VERSION 5.7 ;
  NOWIREEXTENSIONATPIN ON ;
  DIVIDERCHAR "/" ;
  BUSBITCHARS "[]" ;
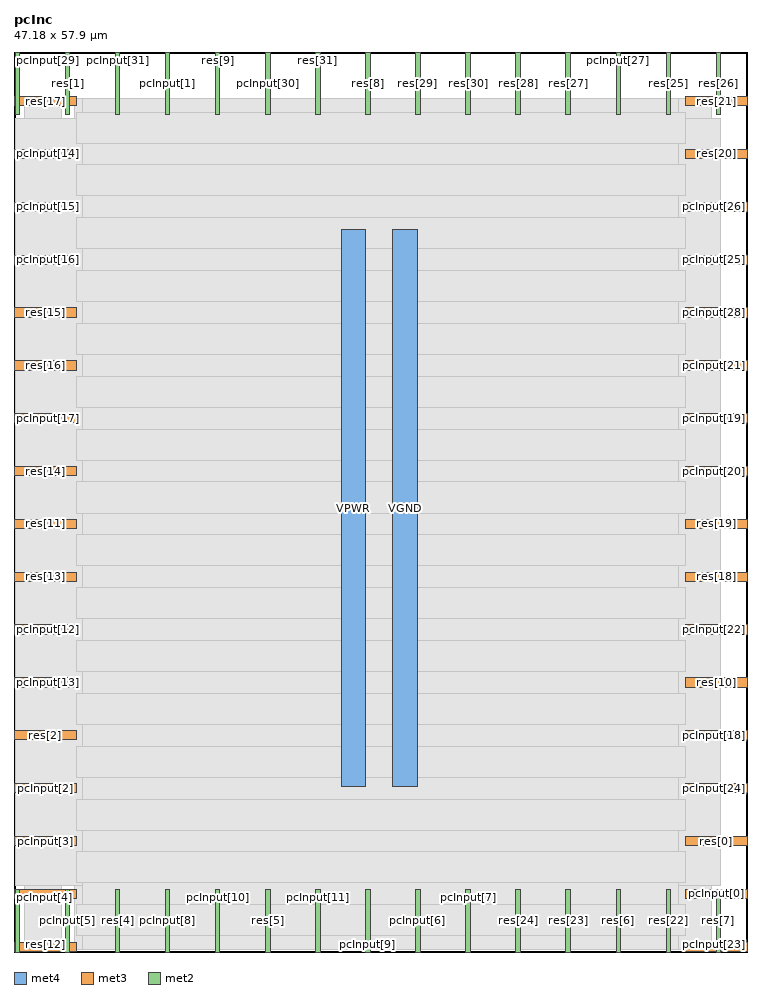
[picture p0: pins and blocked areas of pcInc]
MACRO pcInc
  CLASS BLOCK ;
  FOREIGN pcInc ;
  ORIGIN 0.000 0.000 ;
  SIZE 47.180 BY 57.900 ;
  PIN VGND
    DIRECTION INOUT ;
    USE GROUND ;
    PORT
      LAYER met4 ;
        RECT 24.340 10.640 25.940 46.480 ;
    END
  END VGND
  PIN VPWR
    DIRECTION INOUT ;
    USE POWER ;
    PORT
      LAYER met4 ;
        RECT 21.040 10.640 22.640 46.480 ;
    END
  END VPWR
  PIN pcInput[0]
    DIRECTION INPUT ;
    USE SIGNAL ;
    ANTENNAGATEAREA 0.196500 ;
    PORT
      LAYER met3 ;
        RECT 43.180 3.440 47.180 4.040 ;
    END
  END pcInput[0]
  PIN pcInput[10]
    DIRECTION INPUT ;
    USE SIGNAL ;
    ANTENNAGATEAREA 0.196500 ;
    PORT
      LAYER met2 ;
        RECT 12.970 0.000 13.250 4.000 ;
    END
  END pcInput[10]
  PIN pcInput[11]
    DIRECTION INPUT ;
    USE SIGNAL ;
    ANTENNAGATEAREA 0.196500 ;
    PORT
      LAYER met2 ;
        RECT 19.410 0.000 19.690 4.000 ;
    END
  END pcInput[11]
  PIN pcInput[12]
    DIRECTION INPUT ;
    USE SIGNAL ;
    ANTENNAGATEAREA 0.196500 ;
    PORT
      LAYER met3 ;
        RECT 0.000 20.440 4.000 21.040 ;
    END
  END pcInput[12]
  PIN pcInput[13]
    DIRECTION INPUT ;
    USE SIGNAL ;
    ANTENNAGATEAREA 0.196500 ;
    PORT
      LAYER met3 ;
        RECT 0.000 17.040 4.000 17.640 ;
    END
  END pcInput[13]
  PIN pcInput[14]
    DIRECTION INPUT ;
    USE SIGNAL ;
    ANTENNAGATEAREA 0.196500 ;
    PORT
      LAYER met3 ;
        RECT 0.000 51.040 4.000 51.640 ;
    END
  END pcInput[14]
  PIN pcInput[15]
    DIRECTION INPUT ;
    USE SIGNAL ;
    ANTENNAGATEAREA 0.196500 ;
    PORT
      LAYER met3 ;
        RECT 0.000 47.640 4.000 48.240 ;
    END
  END pcInput[15]
  PIN pcInput[16]
    DIRECTION INPUT ;
    USE SIGNAL ;
    ANTENNAGATEAREA 0.196500 ;
    PORT
      LAYER met3 ;
        RECT 0.000 44.240 4.000 44.840 ;
    END
  END pcInput[16]
  PIN pcInput[17]
    DIRECTION INPUT ;
    USE SIGNAL ;
    ANTENNAGATEAREA 0.196500 ;
    PORT
      LAYER met3 ;
        RECT 0.000 34.040 4.000 34.640 ;
    END
  END pcInput[17]
  PIN pcInput[18]
    DIRECTION INPUT ;
    USE SIGNAL ;
    ANTENNAGATEAREA 0.196500 ;
    PORT
      LAYER met3 ;
        RECT 43.180 13.640 47.180 14.240 ;
    END
  END pcInput[18]
  PIN pcInput[19]
    DIRECTION INPUT ;
    USE SIGNAL ;
    ANTENNAGATEAREA 0.196500 ;
    PORT
      LAYER met3 ;
        RECT 43.180 34.040 47.180 34.640 ;
    END
  END pcInput[19]
  PIN pcInput[1]
    DIRECTION INPUT ;
    USE SIGNAL ;
    ANTENNAGATEAREA 0.196500 ;
    PORT
      LAYER met2 ;
        RECT 9.750 53.900 10.030 57.900 ;
    END
  END pcInput[1]
  PIN pcInput[20]
    DIRECTION INPUT ;
    USE SIGNAL ;
    ANTENNAGATEAREA 0.196500 ;
    PORT
      LAYER met3 ;
        RECT 43.180 30.640 47.180 31.240 ;
    END
  END pcInput[20]
  PIN pcInput[21]
    DIRECTION INPUT ;
    USE SIGNAL ;
    ANTENNAGATEAREA 0.196500 ;
    PORT
      LAYER met3 ;
        RECT 43.180 37.440 47.180 38.040 ;
    END
  END pcInput[21]
  PIN pcInput[22]
    DIRECTION INPUT ;
    USE SIGNAL ;
    ANTENNAGATEAREA 0.196500 ;
    PORT
      LAYER met3 ;
        RECT 43.180 20.440 47.180 21.040 ;
    END
  END pcInput[22]
  PIN pcInput[23]
    DIRECTION INPUT ;
    USE SIGNAL ;
    ANTENNAGATEAREA 0.196500 ;
    PORT
      LAYER met3 ;
        RECT 43.180 0.040 47.180 0.640 ;
    END
  END pcInput[23]
  PIN pcInput[24]
    DIRECTION INPUT ;
    USE SIGNAL ;
    ANTENNAGATEAREA 0.196500 ;
    PORT
      LAYER met3 ;
        RECT 43.180 10.240 47.180 10.840 ;
    END
  END pcInput[24]
  PIN pcInput[25]
    DIRECTION INPUT ;
    USE SIGNAL ;
    ANTENNAGATEAREA 0.196500 ;
    PORT
      LAYER met3 ;
        RECT 43.180 44.240 47.180 44.840 ;
    END
  END pcInput[25]
  PIN pcInput[26]
    DIRECTION INPUT ;
    USE SIGNAL ;
    ANTENNAGATEAREA 0.196500 ;
    PORT
      LAYER met3 ;
        RECT 43.180 47.640 47.180 48.240 ;
    END
  END pcInput[26]
  PIN pcInput[27]
    DIRECTION INPUT ;
    USE SIGNAL ;
    ANTENNAGATEAREA 0.196500 ;
    PORT
      LAYER met2 ;
        RECT 38.730 53.900 39.010 57.900 ;
    END
  END pcInput[27]
  PIN pcInput[28]
    DIRECTION INPUT ;
    USE SIGNAL ;
    ANTENNAGATEAREA 0.196500 ;
    PORT
      LAYER met3 ;
        RECT 43.180 40.840 47.180 41.440 ;
    END
  END pcInput[28]
  PIN pcInput[29]
    DIRECTION INPUT ;
    USE SIGNAL ;
    ANTENNAGATEAREA 0.196500 ;
    PORT
      LAYER met2 ;
        RECT 0.090 53.900 0.370 57.900 ;
    END
  END pcInput[29]
  PIN pcInput[2]
    DIRECTION INPUT ;
    USE SIGNAL ;
    ANTENNAGATEAREA 0.126000 ;
    PORT
      LAYER met3 ;
        RECT 0.000 10.240 4.000 10.840 ;
    END
  END pcInput[2]
  PIN pcInput[30]
    DIRECTION INPUT ;
    USE SIGNAL ;
    ANTENNAGATEAREA 0.196500 ;
    PORT
      LAYER met2 ;
        RECT 16.190 53.900 16.470 57.900 ;
    END
  END pcInput[30]
  PIN pcInput[31]
    DIRECTION INPUT ;
    USE SIGNAL ;
    ANTENNAGATEAREA 0.196500 ;
    PORT
      LAYER met2 ;
        RECT 6.530 53.900 6.810 57.900 ;
    END
  END pcInput[31]
  PIN pcInput[3]
    DIRECTION INPUT ;
    USE SIGNAL ;
    ANTENNAGATEAREA 0.196500 ;
    PORT
      LAYER met3 ;
        RECT 0.000 6.840 4.000 7.440 ;
    END
  END pcInput[3]
  PIN pcInput[4]
    DIRECTION INPUT ;
    USE SIGNAL ;
    ANTENNAGATEAREA 0.196500 ;
    PORT
      LAYER met2 ;
        RECT 0.090 0.000 0.370 4.000 ;
    END
  END pcInput[4]
  PIN pcInput[5]
    DIRECTION INPUT ;
    USE SIGNAL ;
    ANTENNAGATEAREA 0.196500 ;
    PORT
      LAYER met2 ;
        RECT 3.310 0.000 3.590 4.000 ;
    END
  END pcInput[5]
  PIN pcInput[6]
    DIRECTION INPUT ;
    USE SIGNAL ;
    ANTENNAGATEAREA 0.196500 ;
    PORT
      LAYER met2 ;
        RECT 25.850 0.000 26.130 4.000 ;
    END
  END pcInput[6]
  PIN pcInput[7]
    DIRECTION INPUT ;
    USE SIGNAL ;
    ANTENNAGATEAREA 0.196500 ;
    PORT
      LAYER met2 ;
        RECT 29.070 0.000 29.350 4.000 ;
    END
  END pcInput[7]
  PIN pcInput[8]
    DIRECTION INPUT ;
    USE SIGNAL ;
    ANTENNAGATEAREA 0.196500 ;
    PORT
      LAYER met2 ;
        RECT 9.750 0.000 10.030 4.000 ;
    END
  END pcInput[8]
  PIN pcInput[9]
    DIRECTION INPUT ;
    USE SIGNAL ;
    ANTENNAGATEAREA 0.196500 ;
    PORT
      LAYER met2 ;
        RECT 22.630 0.000 22.910 4.000 ;
    END
  END pcInput[9]
  PIN res[0]
    DIRECTION OUTPUT ;
    USE SIGNAL ;
    ANTENNADIFFAREA 0.445500 ;
    PORT
      LAYER met3 ;
        RECT 43.180 6.840 47.180 7.440 ;
    END
  END res[0]
  PIN res[10]
    DIRECTION OUTPUT ;
    USE SIGNAL ;
    ANTENNADIFFAREA 0.445500 ;
    PORT
      LAYER met3 ;
        RECT 43.180 17.040 47.180 17.640 ;
    END
  END res[10]
  PIN res[11]
    DIRECTION OUTPUT ;
    USE SIGNAL ;
    ANTENNADIFFAREA 0.445500 ;
    PORT
      LAYER met3 ;
        RECT 0.000 27.240 4.000 27.840 ;
    END
  END res[11]
  PIN res[12]
    DIRECTION OUTPUT ;
    USE SIGNAL ;
    ANTENNADIFFAREA 0.445500 ;
    PORT
      LAYER met3 ;
        RECT 0.000 0.040 4.000 0.640 ;
    END
  END res[12]
  PIN res[13]
    DIRECTION OUTPUT ;
    USE SIGNAL ;
    ANTENNADIFFAREA 0.445500 ;
    PORT
      LAYER met3 ;
        RECT 0.000 23.840 4.000 24.440 ;
    END
  END res[13]
  PIN res[14]
    DIRECTION OUTPUT ;
    USE SIGNAL ;
    ANTENNADIFFAREA 0.445500 ;
    PORT
      LAYER met3 ;
        RECT 0.000 30.640 4.000 31.240 ;
    END
  END res[14]
  PIN res[15]
    DIRECTION OUTPUT ;
    USE SIGNAL ;
    ANTENNADIFFAREA 0.445500 ;
    PORT
      LAYER met3 ;
        RECT 0.000 40.840 4.000 41.440 ;
    END
  END res[15]
  PIN res[16]
    DIRECTION OUTPUT ;
    USE SIGNAL ;
    ANTENNADIFFAREA 0.445500 ;
    PORT
      LAYER met3 ;
        RECT 0.000 37.440 4.000 38.040 ;
    END
  END res[16]
  PIN res[17]
    DIRECTION OUTPUT ;
    USE SIGNAL ;
    ANTENNADIFFAREA 0.445500 ;
    PORT
      LAYER met3 ;
        RECT 0.000 54.440 4.000 55.040 ;
    END
  END res[17]
  PIN res[18]
    DIRECTION OUTPUT ;
    USE SIGNAL ;
    ANTENNADIFFAREA 0.445500 ;
    PORT
      LAYER met3 ;
        RECT 43.180 23.840 47.180 24.440 ;
    END
  END res[18]
  PIN res[19]
    DIRECTION OUTPUT ;
    USE SIGNAL ;
    ANTENNADIFFAREA 0.445500 ;
    PORT
      LAYER met3 ;
        RECT 43.180 27.240 47.180 27.840 ;
    END
  END res[19]
  PIN res[1]
    DIRECTION OUTPUT ;
    USE SIGNAL ;
    ANTENNADIFFAREA 0.445500 ;
    PORT
      LAYER met2 ;
        RECT 3.310 53.900 3.590 57.900 ;
    END
  END res[1]
  PIN res[20]
    DIRECTION OUTPUT ;
    USE SIGNAL ;
    ANTENNADIFFAREA 0.445500 ;
    PORT
      LAYER met3 ;
        RECT 43.180 51.040 47.180 51.640 ;
    END
  END res[20]
  PIN res[21]
    DIRECTION OUTPUT ;
    USE SIGNAL ;
    ANTENNADIFFAREA 0.445500 ;
    PORT
      LAYER met3 ;
        RECT 43.180 54.440 47.180 55.040 ;
    END
  END res[21]
  PIN res[22]
    DIRECTION OUTPUT ;
    USE SIGNAL ;
    ANTENNADIFFAREA 0.445500 ;
    PORT
      LAYER met2 ;
        RECT 41.950 0.000 42.230 4.000 ;
    END
  END res[22]
  PIN res[23]
    DIRECTION OUTPUT ;
    USE SIGNAL ;
    ANTENNADIFFAREA 0.445500 ;
    PORT
      LAYER met2 ;
        RECT 35.510 0.000 35.790 4.000 ;
    END
  END res[23]
  PIN res[24]
    DIRECTION OUTPUT ;
    USE SIGNAL ;
    ANTENNADIFFAREA 0.445500 ;
    PORT
      LAYER met2 ;
        RECT 32.290 0.000 32.570 4.000 ;
    END
  END res[24]
  PIN res[25]
    DIRECTION OUTPUT ;
    USE SIGNAL ;
    ANTENNADIFFAREA 0.445500 ;
    PORT
      LAYER met2 ;
        RECT 41.950 53.900 42.230 57.900 ;
    END
  END res[25]
  PIN res[26]
    DIRECTION OUTPUT ;
    USE SIGNAL ;
    ANTENNADIFFAREA 0.445500 ;
    PORT
      LAYER met2 ;
        RECT 45.170 53.900 45.450 57.900 ;
    END
  END res[26]
  PIN res[27]
    DIRECTION OUTPUT ;
    USE SIGNAL ;
    ANTENNADIFFAREA 0.445500 ;
    PORT
      LAYER met2 ;
        RECT 35.510 53.900 35.790 57.900 ;
    END
  END res[27]
  PIN res[28]
    DIRECTION OUTPUT ;
    USE SIGNAL ;
    ANTENNADIFFAREA 0.445500 ;
    PORT
      LAYER met2 ;
        RECT 32.290 53.900 32.570 57.900 ;
    END
  END res[28]
  PIN res[29]
    DIRECTION OUTPUT ;
    USE SIGNAL ;
    ANTENNADIFFAREA 0.445500 ;
    PORT
      LAYER met2 ;
        RECT 25.850 53.900 26.130 57.900 ;
    END
  END res[29]
  PIN res[2]
    DIRECTION OUTPUT ;
    USE SIGNAL ;
    ANTENNADIFFAREA 0.445500 ;
    PORT
      LAYER met3 ;
        RECT 0.000 13.640 4.000 14.240 ;
    END
  END res[2]
  PIN res[30]
    DIRECTION OUTPUT ;
    USE SIGNAL ;
    ANTENNADIFFAREA 0.445500 ;
    PORT
      LAYER met2 ;
        RECT 29.070 53.900 29.350 57.900 ;
    END
  END res[30]
  PIN res[31]
    DIRECTION OUTPUT ;
    USE SIGNAL ;
    ANTENNADIFFAREA 0.445500 ;
    PORT
      LAYER met2 ;
        RECT 19.410 53.900 19.690 57.900 ;
    END
  END res[31]
  PIN res[3]
    DIRECTION OUTPUT ;
    USE SIGNAL ;
    ANTENNADIFFAREA 0.445500 ;
    PORT
      LAYER met3 ;
        RECT 0.000 3.440 4.000 4.040 ;
    END
  END res[3]
  PIN res[4]
    DIRECTION OUTPUT ;
    USE SIGNAL ;
    ANTENNADIFFAREA 0.445500 ;
    PORT
      LAYER met2 ;
        RECT 6.530 0.000 6.810 4.000 ;
    END
  END res[4]
  PIN res[5]
    DIRECTION OUTPUT ;
    USE SIGNAL ;
    ANTENNADIFFAREA 0.445500 ;
    PORT
      LAYER met2 ;
        RECT 16.190 0.000 16.470 4.000 ;
    END
  END res[5]
  PIN res[6]
    DIRECTION OUTPUT ;
    USE SIGNAL ;
    ANTENNADIFFAREA 0.445500 ;
    PORT
      LAYER met2 ;
        RECT 38.730 0.000 39.010 4.000 ;
    END
  END res[6]
  PIN res[7]
    DIRECTION OUTPUT ;
    USE SIGNAL ;
    ANTENNADIFFAREA 0.445500 ;
    PORT
      LAYER met2 ;
        RECT 45.170 0.000 45.450 4.000 ;
    END
  END res[7]
  PIN res[8]
    DIRECTION OUTPUT ;
    USE SIGNAL ;
    ANTENNADIFFAREA 0.445500 ;
    PORT
      LAYER met2 ;
        RECT 22.630 53.900 22.910 57.900 ;
    END
  END res[8]
  PIN res[9]
    DIRECTION OUTPUT ;
    USE SIGNAL ;
    ANTENNADIFFAREA 0.445500 ;
    PORT
      LAYER met2 ;
        RECT 12.970 53.900 13.250 57.900 ;
    END
  END res[9]
  OBS
      LAYER nwell ;
        RECT 5.330 10.795 41.590 46.430 ;
      LAYER li1 ;
        RECT 5.520 10.795 41.400 46.325 ;
      LAYER met1 ;
        RECT 0.070 5.820 45.470 49.600 ;
      LAYER met2 ;
        RECT 0.650 53.620 3.030 54.925 ;
        RECT 3.870 53.620 6.250 54.925 ;
        RECT 7.090 53.620 9.470 54.925 ;
        RECT 10.310 53.620 12.690 54.925 ;
        RECT 13.530 53.620 15.910 54.925 ;
        RECT 16.750 53.620 19.130 54.925 ;
        RECT 19.970 53.620 22.350 54.925 ;
        RECT 23.190 53.620 25.570 54.925 ;
        RECT 26.410 53.620 28.790 54.925 ;
        RECT 29.630 53.620 32.010 54.925 ;
        RECT 32.850 53.620 35.230 54.925 ;
        RECT 36.070 53.620 38.450 54.925 ;
        RECT 39.290 53.620 41.670 54.925 ;
        RECT 42.510 53.620 44.890 54.925 ;
        RECT 0.100 4.280 45.440 53.620 ;
        RECT 0.650 0.155 3.030 4.280 ;
        RECT 3.870 0.155 6.250 4.280 ;
        RECT 7.090 0.155 9.470 4.280 ;
        RECT 10.310 0.155 12.690 4.280 ;
        RECT 13.530 0.155 15.910 4.280 ;
        RECT 16.750 0.155 19.130 4.280 ;
        RECT 19.970 0.155 22.350 4.280 ;
        RECT 23.190 0.155 25.570 4.280 ;
        RECT 26.410 0.155 28.790 4.280 ;
        RECT 29.630 0.155 32.010 4.280 ;
        RECT 32.850 0.155 35.230 4.280 ;
        RECT 36.070 0.155 38.450 4.280 ;
        RECT 39.290 0.155 41.670 4.280 ;
        RECT 42.510 0.155 44.890 4.280 ;
      LAYER met3 ;
        RECT 4.400 54.040 42.780 54.905 ;
        RECT 3.990 52.040 43.180 54.040 ;
        RECT 4.400 50.640 42.780 52.040 ;
        RECT 3.990 48.640 43.180 50.640 ;
        RECT 4.400 47.240 42.780 48.640 ;
        RECT 3.990 45.240 43.180 47.240 ;
        RECT 4.400 43.840 42.780 45.240 ;
        RECT 3.990 41.840 43.180 43.840 ;
        RECT 4.400 40.440 42.780 41.840 ;
        RECT 3.990 38.440 43.180 40.440 ;
        RECT 4.400 37.040 42.780 38.440 ;
        RECT 3.990 35.040 43.180 37.040 ;
        RECT 4.400 33.640 42.780 35.040 ;
        RECT 3.990 31.640 43.180 33.640 ;
        RECT 4.400 30.240 42.780 31.640 ;
        RECT 3.990 28.240 43.180 30.240 ;
        RECT 4.400 26.840 42.780 28.240 ;
        RECT 3.990 24.840 43.180 26.840 ;
        RECT 4.400 23.440 42.780 24.840 ;
        RECT 3.990 21.440 43.180 23.440 ;
        RECT 4.400 20.040 42.780 21.440 ;
        RECT 3.990 18.040 43.180 20.040 ;
        RECT 4.400 16.640 42.780 18.040 ;
        RECT 3.990 14.640 43.180 16.640 ;
        RECT 4.400 13.240 42.780 14.640 ;
        RECT 3.990 11.240 43.180 13.240 ;
        RECT 4.400 9.840 42.780 11.240 ;
        RECT 3.990 7.840 43.180 9.840 ;
        RECT 4.400 6.440 42.780 7.840 ;
        RECT 3.990 4.440 43.180 6.440 ;
        RECT 4.400 3.040 42.780 4.440 ;
        RECT 3.990 1.040 43.180 3.040 ;
        RECT 4.400 0.175 42.780 1.040 ;
  END
END pcInc
END LIBRARY

